VERSION 5.8 ;
BUSBITCHARS "[]" ;
DIVIDERCHAR "/" ;
UNITS
    DATABASE MICRONS 1000 ;
END UNITS

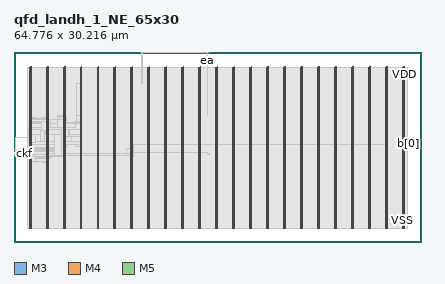
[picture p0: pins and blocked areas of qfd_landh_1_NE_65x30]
MACRO qfd_landh_1_NE_65x30
  FOREIGN qfd_landh_1_NE_65x30 0 0 ;
  CLASS BLOCK ;
  SIZE 64.776 BY 30.216 ;
  PIN a[0]
    DIRECTION INPUT ;
    USE SIGNAL ;
    PORT
      LAYER M3 ;
        RECT  30.708 30.179 30.726 30.216 ;
    END
  END a[0]
  PIN b[0]
    DIRECTION OUTPUT ;
    USE SIGNAL ;
    PORT
      LAYER M4 ;
        RECT  64.692 15.696 64.776 15.72 ;
    END
    PORT
      LAYER M4 ;
        RECT  63.853 15.696 64.716 15.72 ;
    END
  END b[0]
  PIN ck
    DIRECTION INPUT ;
    USE SIGNAL ;
    PORT
      LAYER M4 ;
        RECT  0 13.968 0.084 13.992 ;
    END
  END ck
  PIN ckf
    DIRECTION INPUT ;
    USE SIGNAL ;
    PORT
      LAYER M4 ;
        RECT  0 14.064 0.084 14.088 ;
    END
  END ckf
  PIN ea
    DIRECTION INPUT ;
    USE SIGNAL ;
    PORT
      LAYER M3 ;
        RECT  30.78 30.179 30.798 30.216 ;
    END
  END ea
  PIN fault
    DIRECTION OUTPUT ;
    USE SIGNAL ;
    PORT
      LAYER M4 ;
        RECT  0 14.16 0.084 14.184 ;
    END
  END fault
  PIN k0
    DIRECTION INPUT ;
    USE SIGNAL ;
    PORT
      LAYER M4 ;
        RECT  0 14.256 0.084 14.28 ;
    END
  END k0
  PIN k1
    DIRECTION INPUT ;
    USE SIGNAL ;
    PORT
      LAYER M4 ;
        RECT  0 14.352 0.084 14.376 ;
    END
  END k1
  PIN k2
    DIRECTION INPUT ;
    USE SIGNAL ;
    PORT
      LAYER M4 ;
        RECT  0 14.448 0.084 14.472 ;
    END
  END k2
  PIN rs
    DIRECTION INPUT ;
    USE SIGNAL ;
    PORT
      LAYER M4 ;
        RECT  0 14.544 0.084 14.568 ;
    END
  END rs
  PIN tie_hi
    DIRECTION OUTPUT ;
    USE SIGNAL ;
    PORT
      LAYER M4 ;
        RECT  0 14.64 0.084 14.664 ;
    END
  END tie_hi
  PIN tie_lo
    DIRECTION OUTPUT ;
    USE SIGNAL ;
    PORT
      LAYER M4 ;
        RECT  0 14.736 0.084 14.76 ;
    END
  END tie_lo
  PIN VDD
    DIRECTION INOUT ;
    USE POWER ;
    PORT
      LAYER M5 ;
        RECT  61.992 2.151 62.112 27.833 ;
        RECT  59.292 2.151 59.412 27.833 ;
        RECT  56.592 2.151 56.712 27.833 ;
        RECT  53.892 2.151 54.012 27.833 ;
        RECT  51.192 2.151 51.312 27.833 ;
        RECT  48.492 2.151 48.612 27.833 ;
        RECT  45.792 2.151 45.912 27.833 ;
        RECT  43.092 2.151 43.212 27.833 ;
        RECT  40.392 2.151 40.512 27.833 ;
        RECT  37.692 2.151 37.812 27.833 ;
        RECT  34.992 2.151 35.112 27.833 ;
        RECT  32.292 2.151 32.412 27.833 ;
        RECT  29.592 2.151 29.712 27.833 ;
        RECT  26.892 2.151 27.012 27.833 ;
        RECT  24.192 2.151 24.312 27.833 ;
        RECT  21.492 2.151 21.612 27.833 ;
        RECT  18.792 2.151 18.912 27.833 ;
        RECT  16.092 2.151 16.212 27.833 ;
        RECT  13.392 2.151 13.512 27.833 ;
        RECT  10.692 2.151 10.812 27.833 ;
        RECT  7.992 2.151 8.112 27.833 ;
        RECT  5.292 2.151 5.412 27.833 ;
        RECT  2.592 2.151 2.712 27.833 ;
    END
  END VDD
  PIN VSS
    DIRECTION INOUT ;
    USE GROUND ;
    PORT
      LAYER M5 ;
        RECT  61.8 2.137 61.92 27.819 ;
        RECT  59.1 2.137 59.22 27.819 ;
        RECT  56.4 2.137 56.52 27.819 ;
        RECT  53.7 2.137 53.82 27.819 ;
        RECT  51 2.137 51.12 27.819 ;
        RECT  48.3 2.137 48.42 27.819 ;
        RECT  45.6 2.137 45.72 27.819 ;
        RECT  42.9 2.137 43.02 27.819 ;
        RECT  40.2 2.137 40.32 27.819 ;
        RECT  37.5 2.137 37.62 27.819 ;
        RECT  34.8 2.137 34.92 27.819 ;
        RECT  32.1 2.137 32.22 27.819 ;
        RECT  29.4 2.137 29.52 27.819 ;
        RECT  26.7 2.137 26.82 27.819 ;
        RECT  24 2.137 24.12 27.819 ;
        RECT  21.3 2.137 21.42 27.819 ;
        RECT  18.6 2.137 18.72 27.819 ;
        RECT  15.9 2.137 16.02 27.819 ;
        RECT  13.2 2.137 13.32 27.819 ;
        RECT  10.5 2.137 10.62 27.819 ;
        RECT  7.8 2.137 7.92 27.819 ;
        RECT  5.1 2.137 5.22 27.819 ;
        RECT  2.4 2.137 2.52 27.819 ;
    END
  END VSS
  # OT_OBS_CLOSED layer=M5 d_um=1.536 added=2
  OBS
    LAYER RVTN ;
     RECT  2.16 2.16 62.586 2.295 ;
     RECT  2.16 2.565 62.586 2.835 ;
     RECT  2.16 3.105 62.586 3.375 ;
     RECT  2.16 3.645 62.586 3.915 ;
     RECT  2.16 4.185 62.586 4.455 ;
     RECT  2.16 4.725 62.586 4.995 ;
     RECT  2.16 5.265 62.586 5.535 ;
     RECT  2.16 5.805 62.586 6.075 ;
     RECT  2.16 6.345 62.586 6.615 ;
     RECT  2.16 6.885 62.586 7.155 ;
     RECT  2.16 7.425 62.586 7.695 ;
     RECT  2.16 7.965 62.586 8.235 ;
     RECT  2.16 8.505 62.586 8.775 ;
     RECT  2.16 9.045 62.586 9.315 ;
     RECT  2.16 9.585 62.586 9.855 ;
     RECT  2.16 10.125 62.586 10.395 ;
     RECT  2.16 10.665 62.586 10.935 ;
     RECT  2.16 11.205 62.586 11.475 ;
     RECT  2.16 11.745 62.586 12.015 ;
     RECT  2.16 12.285 62.586 12.555 ;
     RECT  2.16 12.825 62.586 13.095 ;
     RECT  2.16 13.365 62.586 13.635 ;
     RECT  2.16 13.905 62.586 14.175 ;
     RECT  2.16 14.445 62.586 14.715 ;
     RECT  2.16 14.985 62.586 15.255 ;
     RECT  2.16 15.525 62.586 15.795 ;
     RECT  2.16 16.065 62.586 16.335 ;
     RECT  2.16 16.605 62.586 16.875 ;
     RECT  2.16 17.145 62.586 17.415 ;
     RECT  2.16 17.685 62.586 17.955 ;
     RECT  2.16 18.225 62.586 18.495 ;
     RECT  2.16 18.765 62.586 19.035 ;
     RECT  2.16 19.305 62.586 19.575 ;
     RECT  2.16 19.845 62.586 20.115 ;
     RECT  2.16 20.385 62.586 20.655 ;
     RECT  2.16 20.925 62.586 21.195 ;
     RECT  2.16 21.465 62.586 21.735 ;
     RECT  2.16 22.005 62.586 22.275 ;
     RECT  2.16 22.545 62.586 22.815 ;
     RECT  2.16 23.085 62.586 23.355 ;
     RECT  2.16 23.625 62.586 23.895 ;
     RECT  2.16 24.165 62.586 24.435 ;
     RECT  2.16 24.705 62.586 24.975 ;
     RECT  2.16 25.245 62.586 25.515 ;
     RECT  2.16 25.785 62.586 26.055 ;
     RECT  2.16 26.325 62.586 26.595 ;
     RECT  2.16 26.865 62.586 27.135 ;
     RECT  2.16 27.405 62.586 27.675 ;
    LAYER RVTP ;
     RECT  2.16 2.295 62.586 2.565 ;
     RECT  2.16 2.835 62.586 3.105 ;
     RECT  2.16 3.375 62.586 3.645 ;
     RECT  2.16 3.915 62.586 4.185 ;
     RECT  2.16 4.455 62.586 4.725 ;
     RECT  2.16 4.995 62.586 5.265 ;
     RECT  2.16 5.535 62.586 5.805 ;
     RECT  2.16 6.075 62.586 6.345 ;
     RECT  2.16 6.615 62.586 6.885 ;
     RECT  2.16 7.155 62.586 7.425 ;
     RECT  2.16 7.695 62.586 7.965 ;
     RECT  2.16 8.235 62.586 8.505 ;
     RECT  2.16 8.775 62.586 9.045 ;
     RECT  2.16 9.315 62.586 9.585 ;
     RECT  2.16 9.855 62.586 10.125 ;
     RECT  2.16 10.395 62.586 10.665 ;
     RECT  2.16 10.935 62.586 11.205 ;
     RECT  2.16 11.475 62.586 11.745 ;
     RECT  2.16 12.015 62.586 12.285 ;
     RECT  2.16 12.555 62.586 12.825 ;
     RECT  2.16 13.095 62.586 13.365 ;
     RECT  2.16 13.635 62.586 13.905 ;
     RECT  2.16 14.175 62.586 14.445 ;
     RECT  2.16 14.715 62.586 14.985 ;
     RECT  2.16 15.255 62.586 15.525 ;
     RECT  2.16 15.795 62.586 16.065 ;
     RECT  2.16 16.335 62.586 16.605 ;
     RECT  2.16 16.875 62.586 17.145 ;
     RECT  2.16 17.415 62.586 17.685 ;
     RECT  2.16 17.955 62.586 18.225 ;
     RECT  2.16 18.495 62.586 18.765 ;
     RECT  2.16 19.035 62.586 19.305 ;
     RECT  2.16 19.575 62.586 19.845 ;
     RECT  2.16 20.115 62.586 20.385 ;
     RECT  2.16 20.655 62.586 20.925 ;
     RECT  2.16 21.195 62.586 21.465 ;
     RECT  2.16 21.735 62.586 22.005 ;
     RECT  2.16 22.275 62.586 22.545 ;
     RECT  2.16 22.815 62.586 23.085 ;
     RECT  2.16 23.355 62.586 23.625 ;
     RECT  2.16 23.895 62.586 24.165 ;
     RECT  2.16 24.435 62.586 24.705 ;
     RECT  2.16 24.975 62.586 25.245 ;
     RECT  2.16 25.515 62.586 25.785 ;
     RECT  2.16 26.055 62.586 26.325 ;
     RECT  2.16 26.595 62.586 26.865 ;
     RECT  2.16 27.135 62.586 27.405 ;
     RECT  2.16 27.675 62.586 27.81 ;
    LAYER M1 ;
     RECT  2.16 2.151 62.586 27.819 ;
    LAYER M2 ;
     RECT  20.335 30.186 30.775 30.204 ;
     RECT  30.775 30.114 30.875 30.204 ;
     RECT  2.16 2.151 62.586 27.819 ;
     RECT  62.586 15.606 63.887 15.624 ;
    LAYER M3 ;
     RECT  2.415 2.143 2.505 2.413 ;
     RECT  5.115 2.143 5.205 2.413 ;
     RECT  7.815 2.143 7.905 2.413 ;
     RECT  10.515 2.143 10.605 2.413 ;
     RECT  13.215 2.143 13.305 2.413 ;
     RECT  15.915 2.143 16.005 2.413 ;
     RECT  18.615 2.143 18.705 2.413 ;
     RECT  21.315 2.143 21.405 2.413 ;
     RECT  24.015 2.143 24.105 2.413 ;
     RECT  26.715 2.143 26.805 2.413 ;
     RECT  29.415 2.143 29.505 2.413 ;
     RECT  32.115 2.143 32.205 2.413 ;
     RECT  34.815 2.143 34.905 2.413 ;
     RECT  37.515 2.143 37.605 2.413 ;
     RECT  40.215 2.143 40.305 2.413 ;
     RECT  42.915 2.143 43.005 2.413 ;
     RECT  45.615 2.143 45.705 2.413 ;
     RECT  48.315 2.143 48.405 2.413 ;
     RECT  51.015 2.143 51.105 2.413 ;
     RECT  53.715 2.143 53.805 2.413 ;
     RECT  56.415 2.143 56.505 2.413 ;
     RECT  59.115 2.143 59.205 2.413 ;
     RECT  61.815 2.143 61.905 2.413 ;
     RECT  5.115 2.413 5.397 12.631 ;
     RECT  3.492 12.631 3.51 12.757 ;
     RECT  4.716 12.631 5.397 12.757 ;
     RECT  2.415 2.413 2.697 12.793 ;
     RECT  3.492 12.757 5.397 12.793 ;
     RECT  2.415 12.793 5.397 13.333 ;
     RECT  2.415 13.333 5.706 13.441 ;
     RECT  2.415 13.441 6.03 13.579 ;
     RECT  7.815 2.413 8.097 13.639 ;
     RECT  2.34 13.579 6.03 13.675 ;
     RECT  6.84 13.639 8.097 13.675 ;
     RECT  17.46 13.801 17.478 13.981 ;
     RECT  17.46 13.981 17.658 14.093 ;
     RECT  30.744 13.867 31.086 14.099 ;
     RECT  17.46 14.093 17.478 14.141 ;
     RECT  30.744 14.099 30.762 14.189 ;
     RECT  2.34 13.675 8.097 14.341 ;
     RECT  0.144 14.251 0.162 14.429 ;
     RECT  2.304 14.341 8.097 14.611 ;
     RECT  2.304 14.611 8.154 14.783 ;
     RECT  2.376 14.783 8.154 14.909 ;
     RECT  17.856 14.872 17.874 14.909 ;
     RECT  2.415 14.909 8.154 14.953 ;
     RECT  18.615 2.413 18.897 15.019 ;
     RECT  18.615 15.019 18.99 15.059 ;
     RECT  2.415 14.953 8.19 15.061 ;
     RECT  10.515 2.413 10.797 15.151 ;
     RECT  2.415 15.061 8.406 15.457 ;
     RECT  9.792 15.151 10.797 15.457 ;
     RECT  59.115 2.413 59.397 15.457 ;
     RECT  59.112 15.457 59.397 15.533 ;
     RECT  63.864 15.601 63.882 15.725 ;
     RECT  2.415 15.457 10.797 17.041 ;
     RECT  2.376 17.041 10.797 17.879 ;
     RECT  2.376 17.879 9.738 18.257 ;
     RECT  2.415 18.257 9.738 18.769 ;
     RECT  10.515 17.879 10.797 18.769 ;
     RECT  2.415 18.769 10.797 18.959 ;
     RECT  2.415 18.959 8.694 19.067 ;
     RECT  9.648 18.959 10.797 19.103 ;
     RECT  2.415 19.067 5.922 19.139 ;
     RECT  6.66 19.067 8.298 19.265 ;
     RECT  6.732 19.265 8.298 19.499 ;
     RECT  2.415 19.139 5.886 19.535 ;
     RECT  2.415 19.535 5.526 19.643 ;
     RECT  2.415 19.643 3.654 19.769 ;
     RECT  4.392 19.643 5.526 19.769 ;
     RECT  3.636 19.769 3.654 19.841 ;
     RECT  5.115 19.769 5.526 19.841 ;
     RECT  6.948 19.499 8.298 19.913 ;
     RECT  6.948 19.913 8.226 20.039 ;
     RECT  9.864 19.103 10.797 20.047 ;
     RECT  9.864 20.047 10.854 20.147 ;
     RECT  6.948 20.039 6.966 20.183 ;
     RECT  7.74 20.039 8.097 20.183 ;
     RECT  9.864 20.147 10.797 25.169 ;
     RECT  2.415 19.769 2.697 27.557 ;
     RECT  5.115 19.841 5.397 27.557 ;
     RECT  7.815 20.183 8.097 27.557 ;
     RECT  10.515 25.169 10.797 27.557 ;
     RECT  13.215 2.413 13.497 27.557 ;
     RECT  15.915 2.413 16.197 27.557 ;
     RECT  18.615 15.059 18.897 27.557 ;
     RECT  21.315 2.413 21.597 27.557 ;
     RECT  24.015 2.413 24.297 27.557 ;
     RECT  26.715 2.413 26.997 27.557 ;
     RECT  29.415 2.413 29.697 27.557 ;
     RECT  32.115 2.413 32.397 27.557 ;
     RECT  34.815 2.413 35.097 27.557 ;
     RECT  37.515 2.413 37.797 27.557 ;
     RECT  40.215 2.413 40.497 27.557 ;
     RECT  42.915 2.413 43.197 27.557 ;
     RECT  45.615 2.413 45.897 27.557 ;
     RECT  48.315 2.413 48.597 27.557 ;
     RECT  51.015 2.413 51.297 27.557 ;
     RECT  53.715 2.413 53.997 27.557 ;
     RECT  56.415 2.413 56.697 27.557 ;
     RECT  59.115 15.533 59.397 27.557 ;
     RECT  61.815 2.413 62.097 27.557 ;
     RECT  2.607 27.557 2.697 27.827 ;
     RECT  5.307 27.557 5.397 27.827 ;
     RECT  8.007 27.557 8.097 27.827 ;
     RECT  10.707 27.557 10.797 27.827 ;
     RECT  13.407 27.557 13.497 27.827 ;
     RECT  16.107 27.557 16.197 27.827 ;
     RECT  18.807 27.557 18.897 27.827 ;
     RECT  21.507 27.557 21.597 27.827 ;
     RECT  24.207 27.557 24.297 27.827 ;
     RECT  26.907 27.557 26.997 27.827 ;
     RECT  29.607 27.557 29.697 27.827 ;
     RECT  32.307 27.557 32.397 27.827 ;
     RECT  35.007 27.557 35.097 27.827 ;
     RECT  37.707 27.557 37.797 27.827 ;
     RECT  40.407 27.557 40.497 27.827 ;
     RECT  43.107 27.557 43.197 27.827 ;
     RECT  45.807 27.557 45.897 27.827 ;
     RECT  48.507 27.557 48.597 27.827 ;
     RECT  51.207 27.557 51.297 27.827 ;
     RECT  53.907 27.557 53.997 27.827 ;
     RECT  56.607 27.557 56.697 27.827 ;
     RECT  59.307 27.557 59.397 27.827 ;
     RECT  62.007 27.557 62.097 27.827 ;
     RECT  30.708 20.047 30.726 30.109 ;
     RECT  30.708 30.109 30.87 30.179 ;
     RECT  30.726 30.179 30.78 30.204 ;
     RECT  30.798 30.179 30.87 30.204 ;
     RECT  20.34 25.285 20.358 30.209 ;
     RECT  30.852 30.204 30.87 30.209 ;
    LAYER M4 ;
     RECT  0.084 13.968 2.293 13.992 ;
     RECT  0.06 13.992 2.293 14.064 ;
     RECT  0.084 14.064 2.293 14.088 ;
     RECT  0.06 14.088 2.293 14.16 ;
     RECT  0.084 14.16 2.293 14.184 ;
     RECT  0.06 14.184 2.293 14.256 ;
     RECT  0.084 14.256 2.293 14.28 ;
     RECT  0.06 14.28 2.293 14.352 ;
     RECT  0.084 14.352 2.293 14.376 ;
     RECT  0.06 14.376 2.293 14.448 ;
     RECT  0.084 14.448 2.293 14.472 ;
     RECT  0.06 14.472 2.293 14.544 ;
     RECT  0.084 14.544 2.293 14.568 ;
     RECT  0.06 14.568 2.293 14.64 ;
     RECT  0.084 14.64 2.293 14.664 ;
     RECT  0.06 14.664 2.293 14.736 ;
     RECT  0.084 14.736 2.293 14.76 ;
     RECT  2.293 13.872 2.329 14.76 ;
     RECT  2.329 13.584 2.408 14.76 ;
     RECT  0.181 16.608 2.408 16.632 ;
     RECT  2.408 2.148 2.512 27.552 ;
     RECT  2.512 2.418 2.6 27.552 ;
     RECT  2.6 2.418 2.704 27.822 ;
     RECT  2.704 12.864 2.981 14.472 ;
     RECT  2.704 15.84 3.484 17.064 ;
     RECT  2.981 12.864 3.491 13.896 ;
     RECT  3.484 16.032 4.201 17.064 ;
     RECT  4.201 16.032 4.921 17.784 ;
     RECT  3.491 13.584 4.981 13.896 ;
     RECT  4.981 13.584 5.108 14.136 ;
     RECT  4.921 16.032 5.108 18.216 ;
     RECT  4.268 19.2 5.108 19.224 ;
     RECT  5.108 2.148 5.212 27.552 ;
     RECT  5.212 2.418 5.3 27.552 ;
     RECT  5.3 2.418 5.404 27.822 ;
     RECT  5.404 18.192 5.753 19.416 ;
     RECT  5.404 13.68 6.505 14.136 ;
     RECT  5.404 15.984 6.505 17.064 ;
     RECT  5.753 18.816 6.937 19.416 ;
     RECT  6.505 13.68 7.477 17.064 ;
     RECT  6.937 18.192 7.477 19.992 ;
     RECT  7.477 13.68 7.808 19.992 ;
     RECT  7.808 2.148 7.912 27.552 ;
     RECT  7.912 2.418 8 27.552 ;
     RECT  8 2.418 8.104 27.822 ;
     RECT  8.104 15.936 8.237 18.024 ;
     RECT  8.237 15.936 8.705 17.928 ;
     RECT  8.705 15.936 8.849 17.688 ;
     RECT  8.849 15.936 9.137 16.824 ;
     RECT  9.137 16.8 9.173 16.824 ;
     RECT  8.104 13.68 10.508 14.136 ;
     RECT  10.508 2.148 10.612 27.552 ;
     RECT  10.612 2.418 10.7 27.552 ;
     RECT  10.7 2.418 10.804 27.822 ;
     RECT  10.804 13.68 13.208 14.136 ;
     RECT  13.208 2.148 13.312 27.552 ;
     RECT  13.312 2.418 13.4 27.552 ;
     RECT  13.4 2.418 13.504 27.822 ;
     RECT  13.504 13.68 15.908 14.136 ;
     RECT  15.908 2.148 16.012 27.552 ;
     RECT  16.012 2.418 16.1 27.552 ;
     RECT  16.1 2.418 16.204 27.822 ;
     RECT  16.204 13.68 17.845 14.136 ;
     RECT  17.845 13.68 18.608 14.904 ;
     RECT  18.608 2.148 18.712 27.552 ;
     RECT  18.712 2.418 18.8 27.552 ;
     RECT  18.8 2.418 18.904 27.822 ;
     RECT  18.904 13.68 19.043 15.528 ;
     RECT  19.043 14.16 21.308 14.184 ;
     RECT  19.043 15.504 21.308 15.528 ;
     RECT  21.308 2.148 21.412 27.552 ;
     RECT  21.412 2.418 21.5 27.552 ;
     RECT  21.5 2.418 21.604 27.822 ;
     RECT  21.604 14.16 24.008 14.184 ;
     RECT  21.604 15.504 24.008 15.528 ;
     RECT  24.008 2.148 24.112 27.552 ;
     RECT  24.112 2.418 24.2 27.552 ;
     RECT  24.2 2.418 24.304 27.822 ;
     RECT  24.304 14.16 26.708 14.184 ;
     RECT  24.304 15.504 26.708 15.528 ;
     RECT  26.708 2.148 26.812 27.552 ;
     RECT  26.812 2.418 26.9 27.552 ;
     RECT  26.9 2.418 27.004 27.822 ;
     RECT  27.004 14.16 29.408 14.184 ;
     RECT  27.004 15.504 29.408 15.528 ;
     RECT  29.408 2.148 29.512 27.552 ;
     RECT  29.512 2.418 29.6 27.552 ;
     RECT  29.6 2.418 29.704 27.822 ;
     RECT  29.704 14.16 30.733 14.184 ;
     RECT  30.733 13.872 30.773 14.184 ;
     RECT  30.773 13.872 31.097 13.896 ;
     RECT  29.704 15.504 32.108 15.528 ;
     RECT  32.108 2.148 32.212 27.552 ;
     RECT  32.212 2.418 32.3 27.552 ;
     RECT  32.3 2.418 32.404 27.822 ;
     RECT  32.404 15.504 34.808 15.528 ;
     RECT  34.808 2.148 34.912 27.552 ;
     RECT  34.912 2.418 35 27.552 ;
     RECT  35 2.418 35.104 27.822 ;
     RECT  35.104 15.504 37.508 15.528 ;
     RECT  37.508 2.148 37.612 27.552 ;
     RECT  37.612 2.418 37.7 27.552 ;
     RECT  37.7 2.418 37.804 27.822 ;
     RECT  37.804 15.504 40.208 15.528 ;
     RECT  40.208 2.148 40.312 27.552 ;
     RECT  40.312 2.418 40.4 27.552 ;
     RECT  40.4 2.418 40.504 27.822 ;
     RECT  40.504 15.504 42.908 15.528 ;
     RECT  42.908 2.148 43.012 27.552 ;
     RECT  43.012 2.418 43.1 27.552 ;
     RECT  43.1 2.418 43.204 27.822 ;
     RECT  43.204 15.504 45.608 15.528 ;
     RECT  45.608 2.148 45.712 27.552 ;
     RECT  45.712 2.418 45.8 27.552 ;
     RECT  45.8 2.418 45.904 27.822 ;
     RECT  45.904 15.504 48.308 15.528 ;
     RECT  48.308 2.148 48.412 27.552 ;
     RECT  48.412 2.418 48.5 27.552 ;
     RECT  48.5 2.418 48.604 27.822 ;
     RECT  48.604 15.504 51.008 15.528 ;
     RECT  51.008 2.148 51.112 27.552 ;
     RECT  51.112 2.418 51.2 27.552 ;
     RECT  51.2 2.418 51.304 27.822 ;
     RECT  51.304 15.504 53.708 15.528 ;
     RECT  53.708 2.148 53.812 27.552 ;
     RECT  53.812 2.418 53.9 27.552 ;
     RECT  53.9 2.418 54.004 27.822 ;
     RECT  54.004 15.504 56.408 15.528 ;
     RECT  56.408 2.148 56.512 27.552 ;
     RECT  56.512 2.418 56.6 27.552 ;
     RECT  56.6 2.418 56.704 27.822 ;
     RECT  56.704 15.504 59.108 15.528 ;
     RECT  59.108 2.148 59.212 27.552 ;
     RECT  59.212 2.418 59.3 27.552 ;
     RECT  59.3 2.418 59.404 27.822 ;
     RECT  61.808 2.148 61.912 27.552 ;
     RECT  61.912 2.418 62 27.552 ;
     RECT  62 2.418 62.104 27.822 ;
    LAYER M5 ;
     RECT  2.4 2.137 2.52 2.151 ;
     RECT  5.1 2.137 5.22 2.151 ;
     RECT  7.8 2.137 7.92 2.151 ;
     RECT  10.5 2.137 10.62 2.151 ;
     RECT  13.2 2.137 13.32 2.151 ;
     RECT  15.9 2.137 16.02 2.151 ;
     RECT  18.6 2.137 18.72 2.151 ;
     RECT  21.3 2.137 21.42 2.151 ;
     RECT  24 2.137 24.12 2.151 ;
     RECT  26.7 2.137 26.82 2.151 ;
     RECT  29.4 2.137 29.52 2.151 ;
     RECT  32.1 2.137 32.22 2.151 ;
     RECT  34.8 2.137 34.92 2.151 ;
     RECT  37.5 2.137 37.62 2.151 ;
     RECT  40.2 2.137 40.32 2.151 ;
     RECT  42.9 2.137 43.02 2.151 ;
     RECT  45.6 2.137 45.72 2.151 ;
     RECT  48.3 2.137 48.42 2.151 ;
     RECT  51 2.137 51.12 2.151 ;
     RECT  53.7 2.137 53.82 2.151 ;
     RECT  56.4 2.137 56.52 2.151 ;
     RECT  59.1 2.137 59.22 2.151 ;
     RECT  61.8 2.137 61.92 2.151 ;
     RECT  2.4 2.151 2.712 12.853 ;
     RECT  5.1 2.151 5.412 13.573 ;
     RECT  2.4 12.853 3.48 13.619 ;
     RECT  18.6 2.151 18.912 13.669 ;
     RECT  2.4 13.619 2.712 13.861 ;
     RECT  2.304 13.861 2.712 14.003 ;
     RECT  18.6 13.669 19.032 14.053 ;
     RECT  4.992 13.573 5.412 14.147 ;
     RECT  17.856 14.053 19.032 14.915 ;
     RECT  18.6 14.915 19.032 15.539 ;
     RECT  2.4 14.003 2.712 15.829 ;
     RECT  7.8 2.151 8.112 15.925 ;
     RECT  0.192 14.053 0.216 16.643 ;
     RECT  7.8 15.925 9.096 16.835 ;
     RECT  2.4 15.829 3.432 17.075 ;
     RECT  5.1 14.147 5.412 17.077 ;
     RECT  4.992 17.077 5.412 17.749 ;
     RECT  7.8 16.835 8.112 18.181 ;
     RECT  4.32 17.749 5.412 19.235 ;
     RECT  6.96 18.181 8.112 19.427 ;
     RECT  7.296 19.427 8.112 20.003 ;
     RECT  2.4 17.075 2.712 27.819 ;
     RECT  5.1 19.235 5.412 27.819 ;
     RECT  7.8 20.003 8.112 27.819 ;
     RECT  10.5 2.151 10.812 27.819 ;
     RECT  13.2 2.151 13.512 27.819 ;
     RECT  15.9 2.151 16.212 27.819 ;
     RECT  18.6 15.539 18.912 27.819 ;
     RECT  21.3 2.151 21.612 27.819 ;
     RECT  24 2.151 24.312 27.819 ;
     RECT  26.7 2.151 27.012 27.819 ;
     RECT  29.4 2.151 29.712 27.819 ;
     RECT  32.1 2.151 32.412 27.819 ;
     RECT  34.8 2.151 35.112 27.819 ;
     RECT  37.5 2.151 37.812 27.819 ;
     RECT  40.2 2.151 40.512 27.819 ;
     RECT  42.9 2.151 43.212 27.819 ;
     RECT  45.6 2.151 45.912 27.819 ;
     RECT  48.3 2.151 48.612 27.819 ;
     RECT  51 2.151 51.312 27.819 ;
     RECT  53.7 2.151 54.012 27.819 ;
     RECT  56.4 2.151 56.712 27.819 ;
     RECT  59.1 2.151 59.412 27.819 ;
     RECT  61.8 2.151 62.112 27.819 ;
     RECT  2.592 27.819 2.712 27.833 ;
     RECT  5.292 27.819 5.412 27.833 ;
     RECT  7.992 27.819 8.112 27.833 ;
     RECT  10.692 27.819 10.812 27.833 ;
     RECT  13.392 27.819 13.512 27.833 ;
     RECT  16.092 27.819 16.212 27.833 ;
     RECT  18.792 27.819 18.912 27.833 ;
     RECT  21.492 27.819 21.612 27.833 ;
     RECT  24.192 27.819 24.312 27.833 ;
     RECT  26.892 27.819 27.012 27.833 ;
     RECT  29.592 27.819 29.712 27.833 ;
     RECT  32.292 27.819 32.412 27.833 ;
     RECT  34.992 27.819 35.112 27.833 ;
     RECT  37.692 27.819 37.812 27.833 ;
     RECT  40.392 27.819 40.512 27.833 ;
     RECT  43.092 27.819 43.212 27.833 ;
     RECT  45.792 27.819 45.912 27.833 ;
     RECT  48.492 27.819 48.612 27.833 ;
     RECT  51.192 27.819 51.312 27.833 ;
     RECT  53.892 27.819 54.012 27.833 ;
     RECT  56.592 27.819 56.712 27.833 ;
     RECT  59.292 27.819 59.412 27.833 ;
     RECT  61.992 27.819 62.112 27.833 ;
     RECT  3.48 13.573 4.992 13.619 ;
     RECT  9.096 15.925 10.5 16.835 ;
  END
END qfd_landh_1_NE_65x30
END LIBRARY
